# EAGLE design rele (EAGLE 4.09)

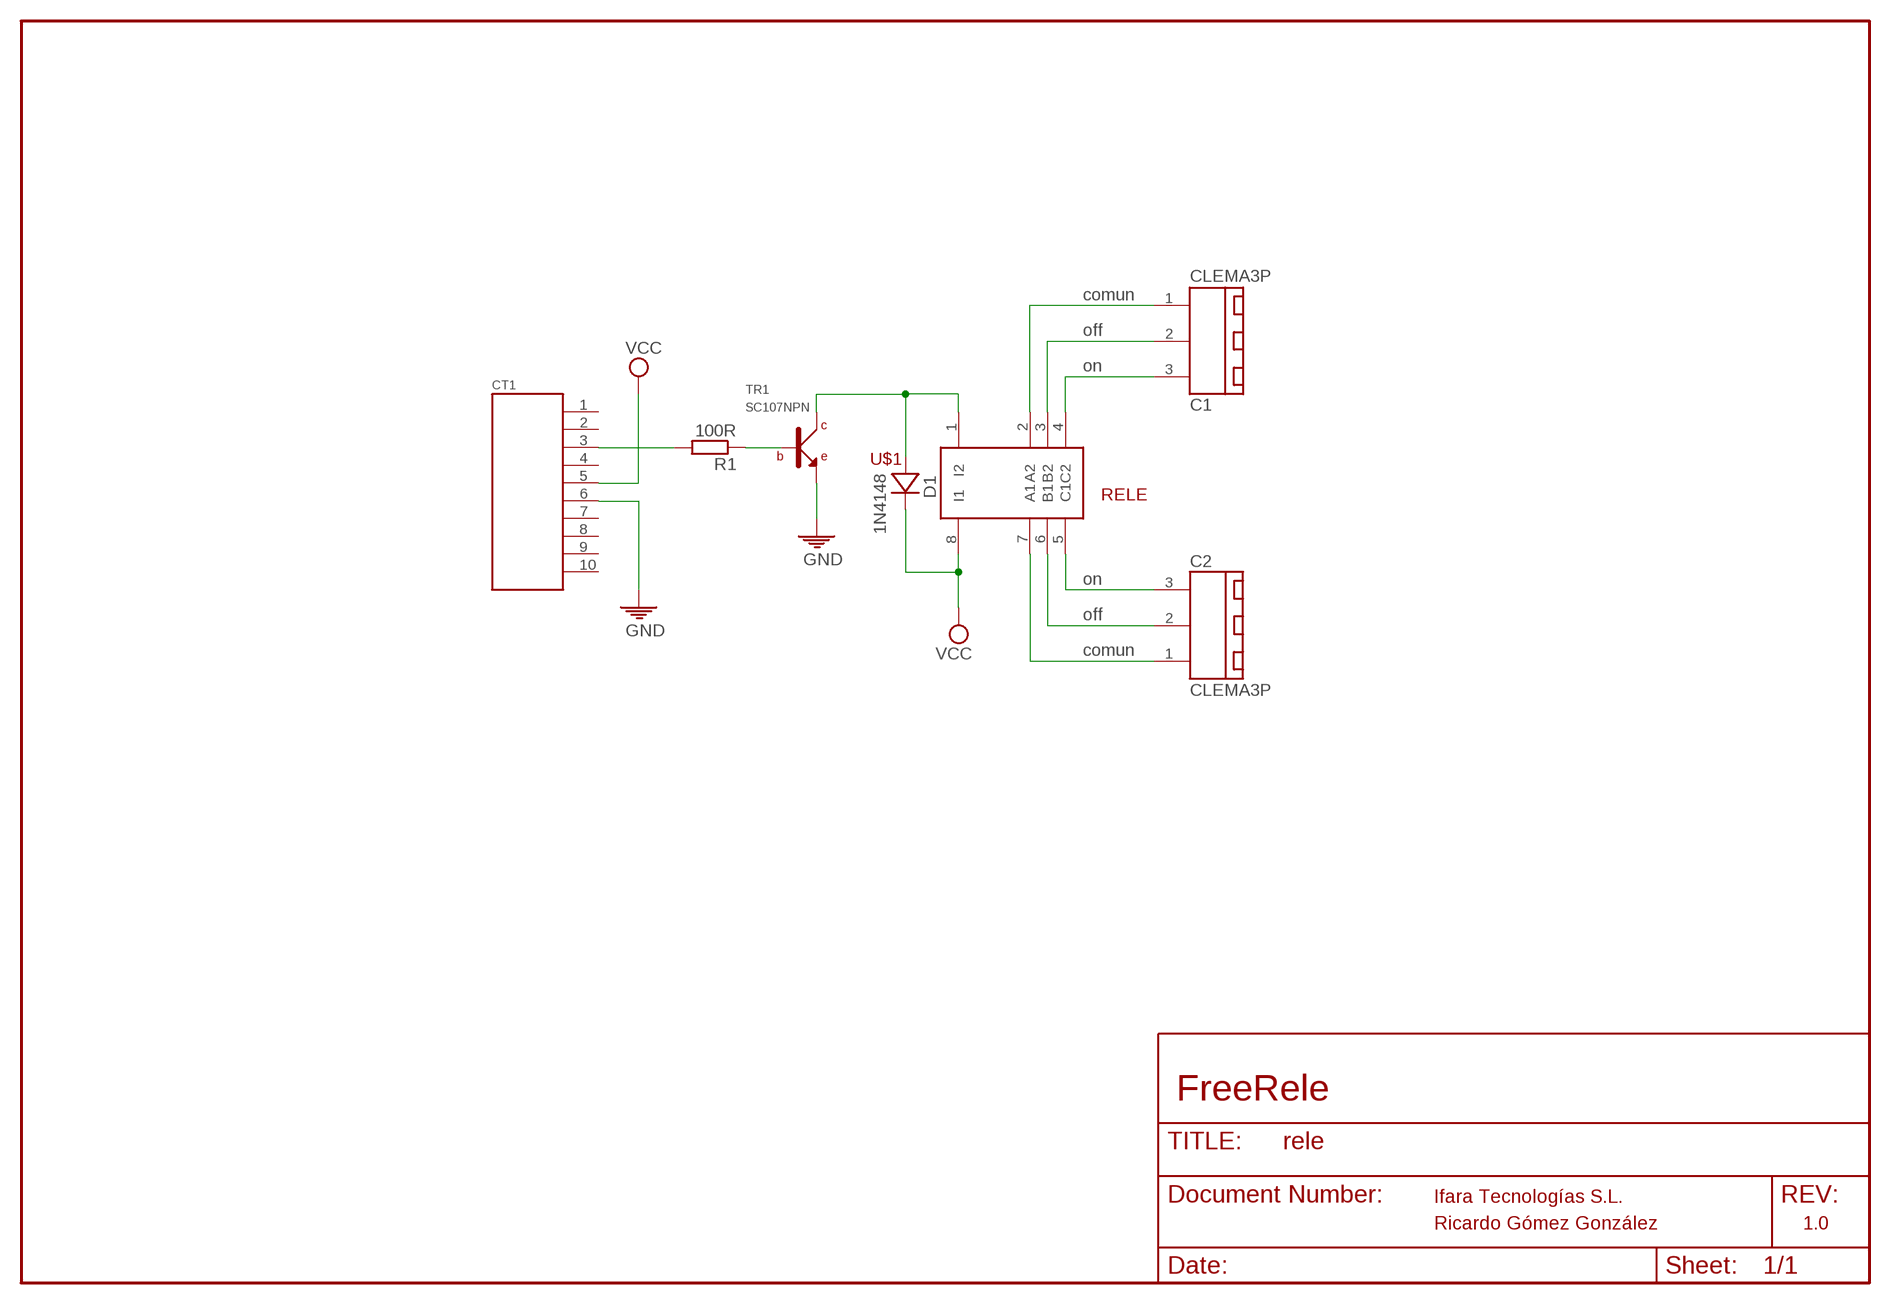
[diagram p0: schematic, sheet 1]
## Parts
C1  CLEMA3P  [C3P]
C2  CLEMA3P  [C3P]
CT1  CTCONA  [CTCON]
D1  1N4148  [DIODO]
R1  100R  RESISTENCIA10  [R207/10]
TR1  SC107NPN  [TRT-NPN]
U$1  RELE  [RELE]

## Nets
GND: CT1.6 TR1.E
N$1: D1.A TR1.C U$1.1(I2)
N$5: R1.1 TR1.B
N$6: C2.2 U$1.6(B1)
N$7: C2.3 U$1.5(C1)
N$8: C2.1 U$1.7(A1)
N$9: C1.1 U$1.2(A2)
N$10: C1.2 U$1.3(B2)
N$11: C1.3 U$1.4(C2)
N$12: CT1.3 R1.2
VCC: CT1.5 D1.K(C) U$1.8(I1)
Unconnected: CT1.1 CT1.2 CT1.4 CT1.7 CT1.8 CT1.9 CT1.10

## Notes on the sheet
- comun
- off
- on
- on
- off
- comun
- FreeRele
- Ifara Tecnologías S.L.
- Ricardo Gómez González | 1.0

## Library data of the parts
C1 C2 = andres-2002:CLEMA3: clema 3 entradas
CT1 = andres-2002:CTCON: Conector compatible CT
D1 = andres-2002:1N4148: Diodo
R1 = andres-2002:RESISTENCIA: Resistencia
TR1 = andres-2002:SC107: SC107 y equivalente
U$1 = andres-2002:RELE

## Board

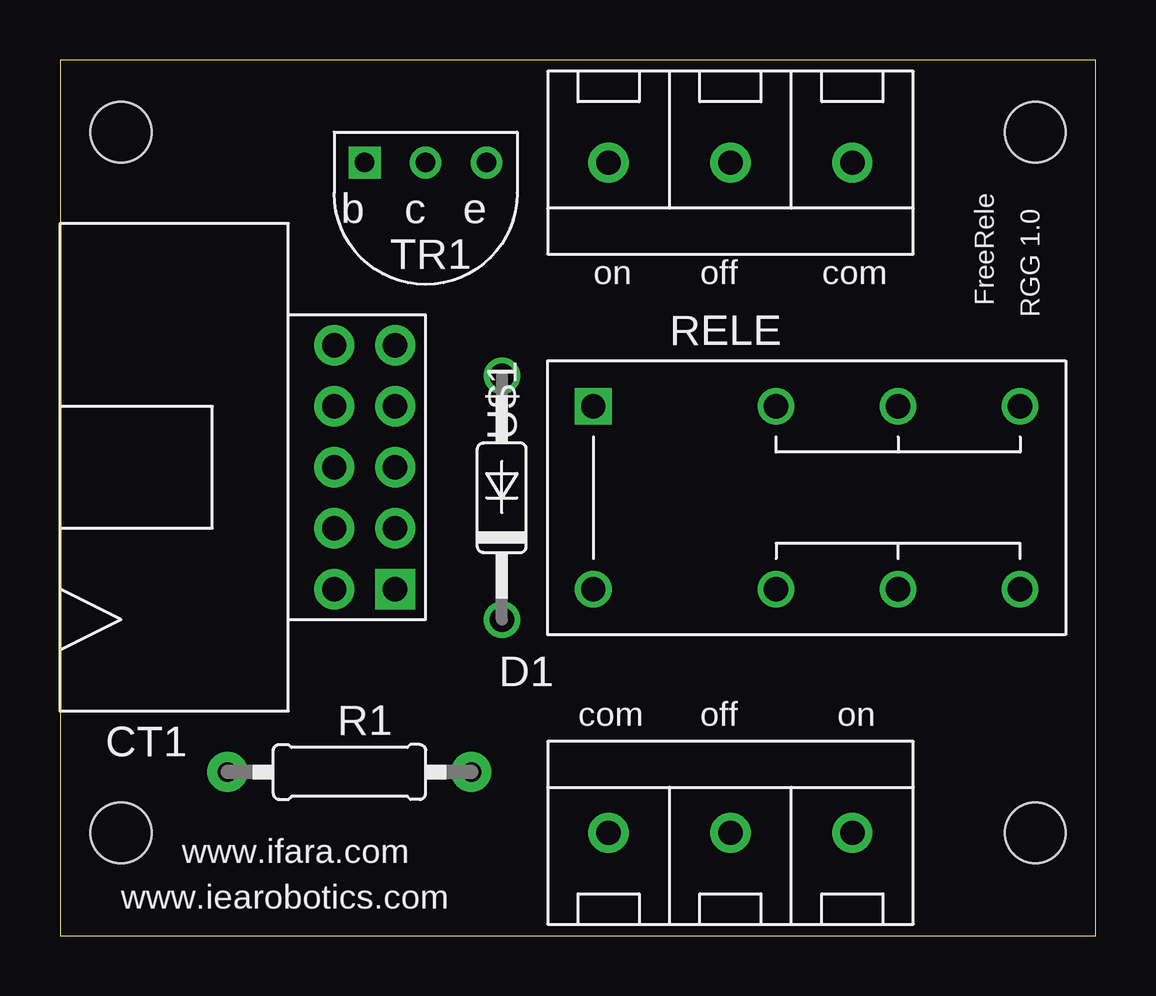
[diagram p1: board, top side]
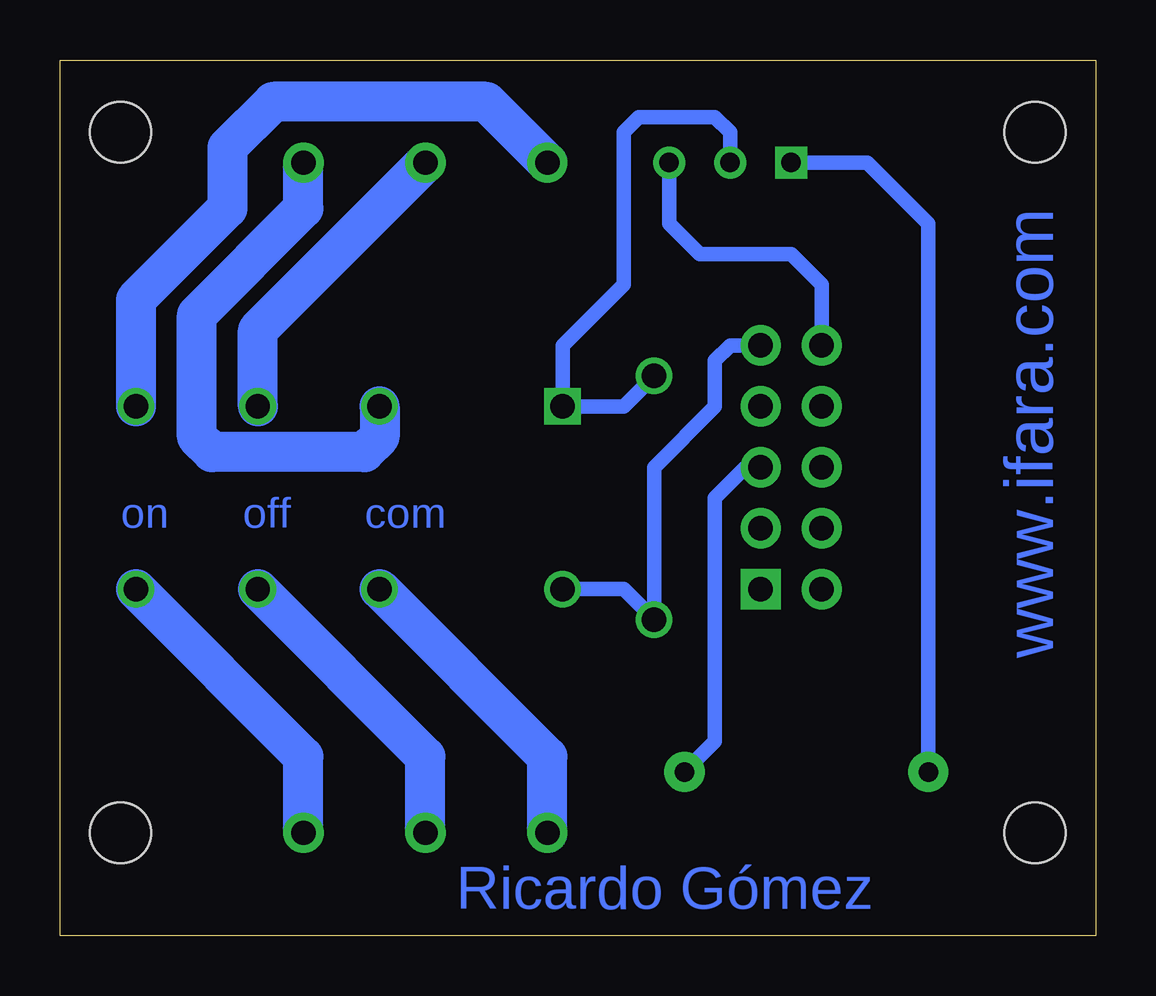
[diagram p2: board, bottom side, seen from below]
Size 43.16 x 36.5 mm. Coordinates in mm from the lower left corner, seen from the top.
Outline: 0,0 43.16,0 43.16,36.5 0,36.5 0,0
Copper layers used: Bottom
Holes 2.54 mm at 2.54,4.28 40.63,33.49 2.54,33.49 40.63,4.28

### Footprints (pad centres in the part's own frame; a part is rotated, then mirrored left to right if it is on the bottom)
C3P = drill 1.016 pad 1.676 round: 1 0,0; 2 5.08,0; 3 10.16,0
CTCON = drill 1.016 pad 1.676 square: 1 0,0 | drill 1.016 pad 1.676 round: 2 2.54,0; 3 5.08,0; 4 7.62,0; 5 10.16,0; 6 10.16,2.54; 7 7.62,2.54; 8 5.08,2.54; 9 2.54,2.54; 10 0,2.54
DIODO = drill 1.016 round: A 10.16,0; K 0,0
R207/10 = drill 0.813 pad 1.676 round: 1 0,0; 2 10.16,0
TRT-NPN = drill 0.813 square: B 1.27,-1.27 | drill 0.813 round: C -1.27,-1.27; E -3.81,-1.27
RELE = drill 1.016 square: 1 0,0 | drill 1.016 round: 2 0,7.62; 3 0,12.7; 4 0,17.78; 5 7.62,17.78; 6 7.62,12.7; 7 7.62,7.62; 8 7.62,0

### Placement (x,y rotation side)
C1  33.02,32.22 180 top
C2  22.86,4.28 0 top
CT1  13.96,14.44 90 top
D1  18.41,13.17 90 top
R1  6.98,6.82 0 top
TR1  13.96,30.95 180 top
U$1  22.22,22.06 270 top

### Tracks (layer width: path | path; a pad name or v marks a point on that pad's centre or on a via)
GND
  Bottom 0.61: CT1.6 11.42,27.14 12.69,28.41 16.51,28.41 17.78,29.68 TR1.E
N$1
  Bottom 0.61: TR1.C 15.23,33.49 15.87,34.12 19.05,34.12 19.68,33.49 19.68,27.14 22.22,24.6 U$1.1 19.68,22.06 D1.A
N$5
  Bottom 0.61: TR1.B 9.52,32.22 6.98,29.68 R1.1
N$6
  Bottom 1.676: C2.2 27.94,7.46 U$1.6
N$7
  Bottom 1.676: C2.3 33.02,7.46 U$1.5
N$8
  Bottom 1.676: C2.1 22.86,7.46 U$1.7
N$9
  Bottom 1.676: C1.1 33.02,30.32 37.46,25.87 37.46,20.79 36.82,20.16 30.48,20.16 29.84,20.79 U$1.2
N$10
  Bottom 1.676: U$1.3 34.92,25.23 C1.2
N$11
  Bottom 1.676: C1.3 25.39,34.76 34.28,34.76 36.19,32.86 36.19,30.32 40,26.51 U$1.4
N$12
  Bottom 0.61: R1.2 15.87,8.09 15.87,18.25 14.6,19.52 CT1.3
VCC
  Bottom 0.61: CT1.5 15.23,24.6 15.87,23.96 15.87,22.06 18.41,19.52 D1.K 19.68,14.44 U$1.8

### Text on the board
Bottom: www.ifara.com | com | off | on | Ricardo Gómez
tPlace: on | off | com | com | off | on | www.ifara.com | www.iearobotics.com
tNames: FreeRele | RGG 1.0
